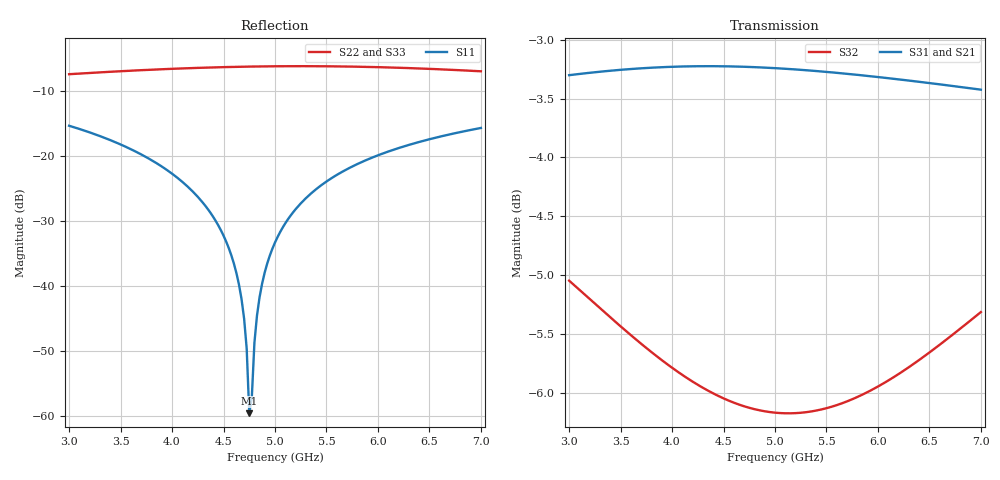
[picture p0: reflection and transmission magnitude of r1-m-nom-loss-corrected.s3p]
! yapnr Order 0 prediction r1-m-nom: predictions/references/r1-m-nom/coarse_dense.s3p, loss-corrected
! substrate M-nom; coupon model OSHPARK-4L-FR408HR; correction: path [('arm', 9.2), ('line', 6.0)]
! |S21|, |S31| (and S12, S13) scaled, phases kept; 50 ohm, e^(+jwt)
# GHz S RI R 50
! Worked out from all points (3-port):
!   161 points, 3 GHz to 7 GHz, reference 50 ohm
!   strongest paths, dB at 3 GHz, 4 GHz, 5 GHz, 6 GHz, 7 GHz:
!     S31: -3.3, -3.2, -3.2, -3.3, -3.4
!     S21: -3.3, -3.2, -3.2, -3.3, -3.4
!     S32: -5.0, -5.8, -6.2, -5.9, -5.3
!   lowest |S11| = -59.6 dB at 4.75 GHz (marker M1), VSWR 1.00, Z = 50.1 + j0.0898 ohm
!   |S11| at or under -10 dB: start of sweep to end of sweep
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3  -0.0771 0.1521  0.0166 -0.6835  0.0166 -0.6835
   0.0167 -0.6837  -0.1603 0.3936  0.099 -0.5504
   0.0167 -0.6837  0.099 -0.5504  -0.1603 0.3936
3.875  -0.0132 0.0843  -0.2968 -0.6218  -0.2968 -0.6218
       -0.2967 -0.622  0.0133 0.4629  -0.0814 -0.5119
       -0.2967 -0.622  -0.0814 -0.5119  0.0133 0.4629
4.4  0.000978 0.0339  -0.4595 -0.5144  -0.4595 -0.5144
     -0.4594 -0.5147  0.1347 0.4601  -0.1659 -0.4725
     -0.4594 -0.5147  -0.1659 -0.4725  0.1347 0.4601
4.65  0.00141 0.0101  -0.5244 -0.4476  -0.5244 -0.4476
      -0.5244 -0.4479  0.192 0.445  -0.2016 -0.4524
      -0.5244 -0.4479  -0.2016 -0.4524  0.192 0.445
4.725  0.000808 0.00319  -0.542 -0.4259  -0.542 -0.4259
       -0.542 -0.4262  0.2087 0.4388  -0.2119 -0.4464
       -0.542 -0.4262  -0.2119 -0.4464  0.2087 0.4388
4.75  0.000536 0.000897  -0.5476 -0.4185  -0.5476 -0.4185
      -0.5476 -0.4188  0.2142 0.4366  -0.2153 -0.4443
      -0.5476 -0.4188  -0.2153 -0.4443  0.2142 0.4366
4.85  -0.000894 -0.00812  -0.5692 -0.3881  -0.5692 -0.3881
      -0.5692 -0.3884  0.2359 0.4268  -0.2287 -0.4362
      -0.5692 -0.3884  -0.2287 -0.4362  0.2359 0.4268
5  -0.00402 -0.0212  -0.5983 -0.3405  -0.5983 -0.3405
   -0.5983 -0.3408  0.2672 0.4096  -0.2486 -0.4239
   -0.5983 -0.3408  -0.2486 -0.4239  0.2672 0.4096
5.65  -0.0286 -0.0696  -0.6754 -0.114  -0.6754 -0.114
      -0.6755 -0.1143  0.3787 0.3071  -0.3336 -0.367
      -0.6755 -0.1143  -0.3336 -0.367  0.3787 0.3071
7  -0.1088 -0.1227  -0.5729 0.3553  -0.5729 0.3553
   -0.5732 0.355  0.4459 0.0382  -0.5096 -0.1853
   -0.5732 0.355  -0.5096 -0.1853  0.4459 0.0382
